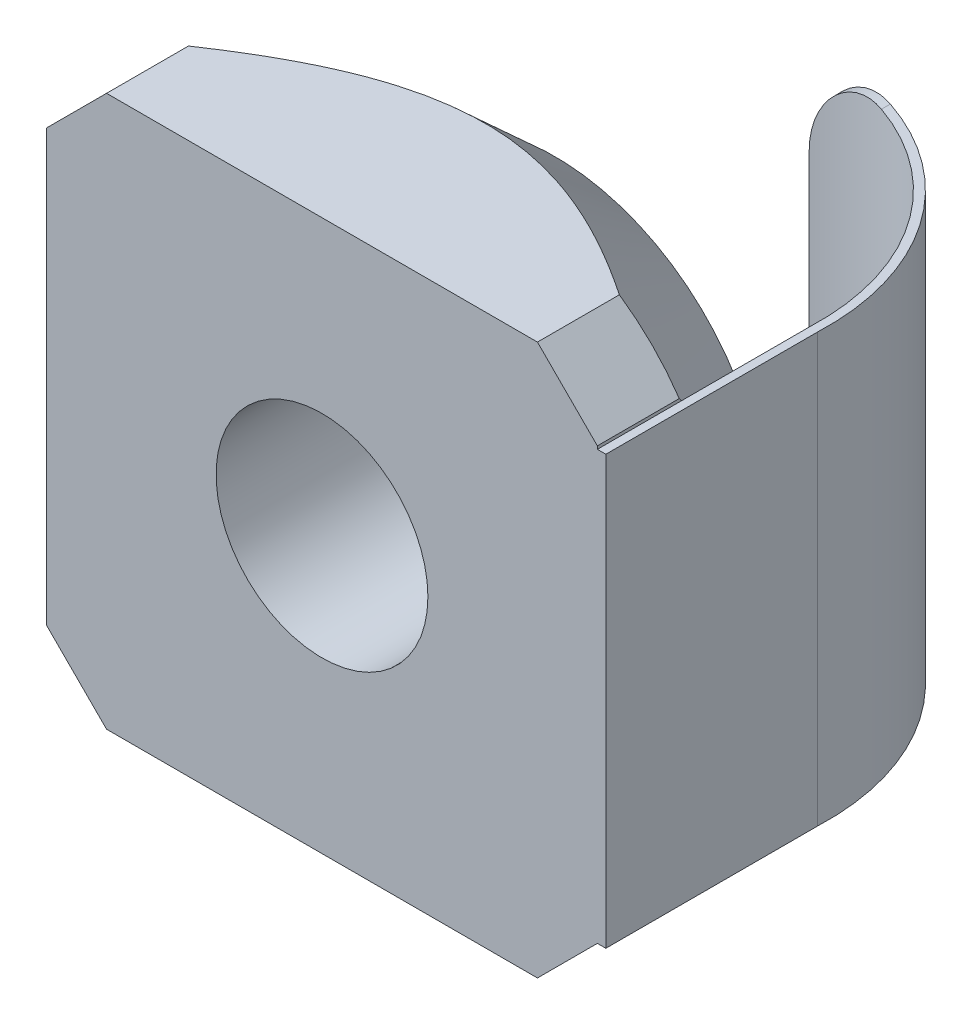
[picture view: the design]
ISO-10303-21;
HEADER;
FILE_DESCRIPTION(('STEP AP214'),'2;1');
FILE_NAME('part.step','',(''),(''),'','','');
FILE_SCHEMA(('AUTOMOTIVE_DESIGN { 1 0 10303 214 1 1 1 1 }'));
ENDSEC;
DATA;
#1=APPLICATION_CONTEXT('core data for automotive mechanical design processes');
#2=APPLICATION_PROTOCOL_DEFINITION('international standard','automotive_design',2000,#1);
#3=PRODUCT_CONTEXT('',#1,'mechanical');
#4=PRODUCT('Part','Part','',(#3));
#5=PRODUCT_RELATED_PRODUCT_CATEGORY('part','',(#4));
#6=PRODUCT_DEFINITION_FORMATION('','',#4);
#7=PRODUCT_DEFINITION_CONTEXT('part definition',#1,'design');
#8=PRODUCT_DEFINITION('design','',#6,#7);
#9=PRODUCT_DEFINITION_SHAPE('','',#8);
#10=(LENGTH_UNIT() NAMED_UNIT(*) SI_UNIT(.MILLI.,.METRE.));
#11=(NAMED_UNIT(*) PLANE_ANGLE_UNIT() SI_UNIT($,.RADIAN.));
#12=(NAMED_UNIT(*) SI_UNIT($,.STERADIAN.) SOLID_ANGLE_UNIT());
#13=UNCERTAINTY_MEASURE_WITH_UNIT(LENGTH_MEASURE(1.E-05),#10,'distance_accuracy_value','');
#14=(GEOMETRIC_REPRESENTATION_CONTEXT(3) GLOBAL_UNCERTAINTY_ASSIGNED_CONTEXT((#13)) GLOBAL_UNIT_ASSIGNED_CONTEXT((#10,
#11,#12)) REPRESENTATION_CONTEXT('',''));
#15=CARTESIAN_POINT('',(0.,0.,0.));
#16=DIRECTION('',(0.,0.,1.));
#17=DIRECTION('',(1.,0.,0.));
#18=AXIS2_PLACEMENT_3D('',#15,#16,#17);
#19=CARTESIAN_POINT('',(0.,0.,-5.5));
#20=DIRECTION('',(0.,0.,1.));
#21=DIRECTION('',(1.,0.,0.));
#22=AXIS2_PLACEMENT_3D('',#19,#20,#21);
#23=PLANE('',#22);
#24=CARTESIAN_POINT('',(0.,0.,-5.5));
#25=DIRECTION('',(0.,0.,1.));
#26=DIRECTION('',(1.,0.,0.));
#27=AXIS2_PLACEMENT_3D('',#24,#25,#26);
#28=CIRCLE('',#27,2.5);
#29=CARTESIAN_POINT('',(2.5,0.,-5.5));
#30=VERTEX_POINT('',#29);
#31=EDGE_CURVE('E327',#30,#30,#28,.T.);
#32=ORIENTED_EDGE('',*,*,#31,.T.);
#33=EDGE_LOOP('',(#32));
#34=FACE_BOUND('',#33,.T.);
#35=CARTESIAN_POINT('',(0.,0.,-5.50000000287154));
#36=DIRECTION('',(0.,0.,1.));
#37=DIRECTION('',(1.,0.,0.));
#38=AXIS2_PLACEMENT_3D('',#35,#36,#37);
#39=CIRCLE('',#38,5.00000000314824);
#40=CARTESIAN_POINT('',(5.00000000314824,0.,-5.50000000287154));
#41=VERTEX_POINT('',#40);
#42=EDGE_CURVE('E288',#41,#41,#39,.T.);
#43=ORIENTED_EDGE('',*,*,#42,.F.);
#44=EDGE_LOOP('',(#43));
#45=FACE_BOUND('',#44,.T.);
#46=ADVANCED_FACE('F30',(#34,#45),#23,.F.);
#47=CARTESIAN_POINT('',(1.13061329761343,-5.08578643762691,-5.23061329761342));
#48=DIRECTION('',(0.,1.,0.));
#49=DIRECTION('',(0.,0.,1.));
#50=AXIS2_PLACEMENT_3D('',#47,#48,#49);
#51=CYLINDRICAL_SURFACE('',#50,5.37433680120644);
#52=DIRECTION('',(0.,1.,0.));
#53=VECTOR('',#52,1.);
#54=CARTESIAN_POINT('',(0.900000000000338,-5.08578643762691,-10.6));
#55=LINE('',#54,#53);
#56=CARTESIAN_POINT('',(0.900000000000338,-3.08578643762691,-10.6));
#57=VERTEX_POINT('',#56);
#58=CARTESIAN_POINT('',(0.900000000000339,3.01421356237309,-10.6));
#59=VERTEX_POINT('',#58);
#60=EDGE_CURVE('E130',#57,#59,#55,.T.);
#61=ORIENTED_EDGE('',*,*,#60,.F.);
#62=CARTESIAN_POINT('',(2.90000000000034,-5.08578643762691,-10.3053316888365));
#63=CARTESIAN_POINT('',(2.84803419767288,-5.08579244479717,-10.3234580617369));
#64=CARTESIAN_POINT('',(2.79577900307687,-5.08376089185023,-10.34077491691));
#65=CARTESIAN_POINT('',(2.69104946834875,-5.07553358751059,-10.3737183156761));
#66=CARTESIAN_POINT('',(2.63857507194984,-5.0693366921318,-10.3893443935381));
#67=CARTESIAN_POINT('',(2.53380993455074,-5.05269177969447,-10.4188209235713));
#68=CARTESIAN_POINT('',(2.48151914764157,-5.04224491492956,-10.4326718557));
#69=CARTESIAN_POINT('',(2.37754341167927,-5.01708267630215,-10.4585706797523));
#70=CARTESIAN_POINT('',(2.32585839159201,-5.00236780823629,-10.4706187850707));
#71=CARTESIAN_POINT('',(2.17211110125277,-4.95174451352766,-10.504107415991));
#72=CARTESIAN_POINT('',(2.07148948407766,-4.90937809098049,-10.5228554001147));
#73=CARTESIAN_POINT('',(1.8778476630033,-4.80832605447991,-10.5536557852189));
#74=CARTESIAN_POINT('',(1.78482256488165,-4.74965105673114,-10.5657125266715));
#75=CARTESIAN_POINT('',(1.61135189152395,-4.61905010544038,-10.5841005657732));
#76=CARTESIAN_POINT('',(1.53066546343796,-4.5474613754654,-10.5905576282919));
#77=CARTESIAN_POINT('',(1.3817294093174,-4.39209571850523,-10.5996001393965));
#78=CARTESIAN_POINT('',(1.31348514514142,-4.30831356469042,-10.602183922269));
#79=CARTESIAN_POINT('',(1.19010431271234,-4.12902241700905,-10.6049836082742));
#80=CARTESIAN_POINT('',(1.13526474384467,-4.03330843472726,-10.605149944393));
#81=CARTESIAN_POINT('',(1.04205250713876,-3.83419182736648,-10.6044227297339));
#82=CARTESIAN_POINT('',(1.00367583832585,-3.7307910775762,-10.6035294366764));
#83=CARTESIAN_POINT('',(0.949511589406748,-3.53731687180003,-10.6019565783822));
#84=CARTESIAN_POINT('',(0.930977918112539,-3.4480009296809,-10.6012666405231));
#85=CARTESIAN_POINT('',(0.906208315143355,-3.26772910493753,-10.6002660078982));
#86=CARTESIAN_POINT('',(0.899965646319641,-3.17677414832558,-10.5999551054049));
#87=CARTESIAN_POINT('',(0.900000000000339,-3.08578643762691,-10.6));
#88=B_SPLINE_CURVE_WITH_KNOTS('',3,(#62,#63,#64,#65,#66,#67,#68,#69,#70,#71,#72,#73,#74,#75,#76,
#77,#78,#79,#80,#81,#82,#83,#84,#85,#86,#87),.UNSPECIFIED.,.F.,.F.,(4,2,2,2,2,2,2,2,2,2,2,2,4),
(0.,0.165074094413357,0.330193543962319,0.495268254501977,0.660323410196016,0.990846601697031,
1.32115513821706,1.64383733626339,1.96665826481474,2.29608914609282,2.625439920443,
2.89827884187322,3.17096816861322),.UNSPECIFIED.);
#89=CARTESIAN_POINT('',(2.90000000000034,-5.08578643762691,-10.3053316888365));
#90=VERTEX_POINT('',#89);
#91=EDGE_CURVE('E136',#90,#57,#88,.T.);
#92=ORIENTED_EDGE('',*,*,#91,.F.);
#93=CARTESIAN_POINT('',(1.13061329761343,-5.08578643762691,-5.23061329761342));
#94=DIRECTION('',(0.,1.,0.));
#95=DIRECTION('',(0.,0.,1.));
#96=AXIS2_PLACEMENT_3D('',#93,#94,#95);
#97=CIRCLE('',#96,5.37433680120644);
#98=CARTESIAN_POINT('',(6.5,-5.08578643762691,-5.));
#99=VERTEX_POINT('',#98);
#100=EDGE_CURVE('E264',#90,#99,#97,.F.);
#101=ORIENTED_EDGE('',*,*,#100,.T.);
#102=DIRECTION('',(0.,1.,0.));
#103=VECTOR('',#102,1.);
#104=CARTESIAN_POINT('',(6.5,-5.08578643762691,-5.00000000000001));
#105=LINE('',#104,#103);
#106=CARTESIAN_POINT('',(6.5,5.01421356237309,-5.00000000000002));
#107=VERTEX_POINT('',#106);
#108=EDGE_CURVE('E137',#107,#99,#105,.F.);
#109=ORIENTED_EDGE('',*,*,#108,.F.);
#110=CARTESIAN_POINT('',(1.13061329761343,5.01421356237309,-5.23061329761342));
#111=DIRECTION('',(0.,1.,0.));
#112=DIRECTION('',(0.,0.,1.));
#113=AXIS2_PLACEMENT_3D('',#110,#111,#112);
#114=CIRCLE('',#113,5.37433680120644);
#115=CARTESIAN_POINT('',(2.90000000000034,5.01421356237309,-10.3053316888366));
#116=VERTEX_POINT('',#115);
#117=EDGE_CURVE('E133',#116,#107,#114,.F.);
#118=ORIENTED_EDGE('',*,*,#117,.F.);
#119=CARTESIAN_POINT('',(0.900000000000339,3.01421356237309,-10.6));
#120=CARTESIAN_POINT('',(0.900000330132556,3.07046535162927,-10.5999949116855));
#121=CARTESIAN_POINT('',(0.902374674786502,3.12669009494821,-10.6001025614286));
#122=CARTESIAN_POINT('',(0.911846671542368,3.23873632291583,-10.6004988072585));
#123=CARTESIAN_POINT('',(0.918944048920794,3.29455783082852,-10.6007873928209));
#124=CARTESIAN_POINT('',(0.947254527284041,3.46073025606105,-10.6018566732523));
#125=CARTESIAN_POINT('',(0.975486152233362,3.56996713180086,-10.6028411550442));
#126=CARTESIAN_POINT('',(1.04988306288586,3.78215272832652,-10.6044710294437));
#127=CARTESIAN_POINT('',(1.0960569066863,3.88509842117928,-10.6051162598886));
#128=CARTESIAN_POINT('',(1.20503246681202,4.08178799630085,-10.6047100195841));
#129=CARTESIAN_POINT('',(1.2678326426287,4.17553272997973,-10.6036587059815));
#130=CARTESIAN_POINT('',(1.40800107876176,4.35081056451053,-10.5982422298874));
#131=CARTESIAN_POINT('',(1.48532101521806,4.43238260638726,-10.593887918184));
#132=CARTESIAN_POINT('',(1.6522600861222,4.58126236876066,-10.58022750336));
#133=CARTESIAN_POINT('',(1.74187515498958,4.64857478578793,-10.5709230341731));
#134=CARTESIAN_POINT('',(1.92817494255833,4.76560487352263,-10.5462505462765));
#135=CARTESIAN_POINT('',(2.02464050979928,4.81570333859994,-10.5310321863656));
#136=CARTESIAN_POINT('',(2.22328367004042,4.89932935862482,-10.4936700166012));
#137=CARTESIAN_POINT('',(2.32546183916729,4.93285523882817,-10.4715255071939));
#138=CARTESIAN_POINT('',(2.50694959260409,4.97686434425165,-10.4263509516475));
#139=CARTESIAN_POINT('',(2.58579039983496,4.99096532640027,-10.4048403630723));
#140=CARTESIAN_POINT('',(2.74330698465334,5.00964641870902,-10.3579469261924));
#141=CARTESIAN_POINT('',(2.82198281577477,5.01424259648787,-10.3325706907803));
#142=CARTESIAN_POINT('',(2.90000000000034,5.01421356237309,-10.3053316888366));
#143=B_SPLINE_CURVE_WITH_KNOTS('',3,(#119,#120,#121,#122,#123,#124,#125,#126,#127,#128,#129,
#130,#131,#132,#133,#134,#135,#136,#137,#138,#139,#140,#141,#142),.UNSPECIFIED.,.F.,.F.,(4,2,2,
2,2,2,2,2,2,2,2,4),(0.,0.168651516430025,0.337293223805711,0.674049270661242,1.01096614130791,
1.3478518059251,1.68363552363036,2.01930847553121,2.34698849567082,2.67470162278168,
2.92287445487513,3.17062741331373),.UNSPECIFIED.);
#144=EDGE_CURVE('E33',#59,#116,#143,.T.);
#145=ORIENTED_EDGE('',*,*,#144,.F.);
#146=EDGE_LOOP('',(#61,#92,#101,#109,#118,#145));
#147=FACE_BOUND('',#146,.T.);
#148=ADVANCED_FACE('F128',(#147),#51,.F.);
#149=CARTESIAN_POINT('',(6.5,-5.08578643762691,0.));
#150=DIRECTION('',(-1.,0.,0.));
#151=DIRECTION('',(0.,0.,1.));
#152=AXIS2_PLACEMENT_3D('',#149,#150,#151);
#153=PLANE('',#152);
#154=ORIENTED_EDGE('',*,*,#108,.T.);
#155=DIRECTION('',(0.,0.,1.));
#156=VECTOR('',#155,1.);
#157=CARTESIAN_POINT('',(6.5,-5.08578643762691,-6.41150462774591));
#158=LINE('',#157,#156);
#159=CARTESIAN_POINT('',(6.5,-5.08578639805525,-1.93333422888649));
#160=VERTEX_POINT('',#159);
#161=EDGE_CURVE('E361',#99,#160,#158,.T.);
#162=ORIENTED_EDGE('',*,*,#161,.T.);
#163=CARTESIAN_POINT('',(6.49999999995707,5.01421356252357,-1.98147651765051));
#164=CARTESIAN_POINT('',(6.49999999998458,4.90089300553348,-2.05735219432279));
#165=CARTESIAN_POINT('',(6.49999999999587,4.78682941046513,-2.13213187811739));
#166=CARTESIAN_POINT('',(6.50000000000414,4.55705300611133,-2.27916665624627));
#167=CARTESIAN_POINT('',(6.50000000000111,4.44133984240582,-2.35142119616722));
#168=CARTESIAN_POINT('',(6.49999999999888,4.2077031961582,-2.49331131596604));
#169=CARTESIAN_POINT('',(6.49999999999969,4.08977293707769,-2.56293578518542));
#170=CARTESIAN_POINT('',(6.50000000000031,3.85200835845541,-2.69883005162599));
#171=CARTESIAN_POINT('',(6.50000000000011,3.73217414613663,-2.76510003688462));
#172=CARTESIAN_POINT('',(6.49999999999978,3.36347781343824,-2.96142749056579));
#173=CARTESIAN_POINT('',(6.49999999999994,3.11129685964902,-3.08537257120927));
#174=CARTESIAN_POINT('',(6.50000000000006,2.59770756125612,-3.31174910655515));
#175=CARTESIAN_POINT('',(6.50000000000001,2.33631394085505,-3.41421322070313));
#176=CARTESIAN_POINT('',(6.49999999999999,1.89822792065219,-3.55997176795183));
#177=CARTESIAN_POINT('',(6.5,1.72423965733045,-3.61138096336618));
#178=CARTESIAN_POINT('',(6.5,1.37277217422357,-3.70067669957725));
#179=CARTESIAN_POINT('',(6.5,1.19529289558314,-3.73856301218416));
#180=CARTESIAN_POINT('',(6.5,0.839667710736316,-3.79880141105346));
#181=CARTESIAN_POINT('',(6.5,0.661549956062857,-3.82131766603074));
#182=CARTESIAN_POINT('',(6.5,0.3040090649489,-3.8503496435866));
#183=CARTESIAN_POINT('',(6.5,0.124586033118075,-3.85686663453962));
#184=CARTESIAN_POINT('',(6.5,-0.234534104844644,-3.85354991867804));
#185=CARTESIAN_POINT('',(6.5,-0.414230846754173,-3.84367725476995));
#186=CARTESIAN_POINT('',(6.5,-0.772032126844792,-3.80803294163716));
#187=CARTESIAN_POINT('',(6.5,-0.950136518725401,-3.78225984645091));
#188=CARTESIAN_POINT('',(6.5,-1.30552029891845,-3.71570927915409));
#189=CARTESIAN_POINT('',(6.5,-1.48276890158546,-3.67476939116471));
#190=CARTESIAN_POINT('',(6.5,-1.83363232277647,-3.57968542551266));
#191=CARTESIAN_POINT('',(6.5,-2.00724719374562,-3.52554153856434));
#192=CARTESIAN_POINT('',(6.5,-2.44147704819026,-3.37423611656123));
#193=CARTESIAN_POINT('',(6.5,-2.69944314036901,-3.2694828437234));
#194=CARTESIAN_POINT('',(6.5,-3.20636233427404,-3.03963560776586));
#195=CARTESIAN_POINT('',(6.5,-3.45530232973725,-2.91451340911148));
#196=CARTESIAN_POINT('',(6.5,-3.9386424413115,-2.65236001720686));
#197=CARTESIAN_POINT('',(6.5,-4.17325100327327,-2.51570956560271));
#198=CARTESIAN_POINT('',(6.5,-4.51960285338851,-2.3026955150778));
#199=CARTESIAN_POINT('',(6.5,-4.63393607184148,-2.23048126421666));
#200=CARTESIAN_POINT('',(6.5,-4.86101206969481,-2.08364094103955));
#201=CARTESIAN_POINT('',(6.5,-4.97375516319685,-2.00901535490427));
#202=CARTESIAN_POINT('',(6.5,-5.08578635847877,-1.93333425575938));
#203=B_SPLINE_CURVE_WITH_KNOTS('',3,(#163,#164,#165,#166,#167,#168,#169,#170,#171,#172,#173,
#174,#175,#176,#177,#178,#179,#180,#181,#182,#183,#184,#185,#186,#187,#188,#189,#190,#191,#192,
#193,#194,#195,#196,#197,#198,#199,#200,#201,#202),.UNSPECIFIED.,.F.,.F.,(4,2,2,2,2,2,2,2,2,2,2,
2,2,2,2,2,2,2,2,4),(0.,0.409135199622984,0.8183596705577,1.2291540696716,1.63992541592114,
2.48215150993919,3.32308765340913,3.86690681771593,4.4107351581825,4.94865991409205,
5.48654202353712,6.02570447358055,6.56491596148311,7.11007693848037,7.6552300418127,
8.48926109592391,9.32445829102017,10.1385545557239,10.5442192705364,10.949802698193),.UNSPECIFIED.);
#204=CARTESIAN_POINT('',(6.5,5.01421356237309,-1.98147651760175));
#205=VERTEX_POINT('',#204);
#206=EDGE_CURVE('E191',#205,#160,#203,.T.);
#207=ORIENTED_EDGE('',*,*,#206,.F.);
#208=DIRECTION('',(0.,0.,1.));
#209=VECTOR('',#208,1.);
#210=CARTESIAN_POINT('',(6.5,5.01421356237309,-6.41150462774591));
#211=LINE('',#210,#209);
#212=EDGE_CURVE('E294',#107,#205,#211,.T.);
#213=ORIENTED_EDGE('',*,*,#212,.F.);
#214=EDGE_LOOP('',(#154,#162,#207,#213));
#215=FACE_BOUND('',#214,.T.);
#216=ADVANCED_FACE('F269',(#215),#153,.T.);
#217=CARTESIAN_POINT('',(2.90000000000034,3.01421356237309,-8.50575231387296));
#218=DIRECTION('',(0.,0.,-1.));
#219=DIRECTION('',(0.,1.,0.));
#220=AXIS2_PLACEMENT_3D('',#217,#218,#219);
#221=CYLINDRICAL_SURFACE('',#220,2.);
#222=ORIENTED_EDGE('',*,*,#144,.T.);
#223=DIRECTION('',(0.,0.,1.));
#224=VECTOR('',#223,1.);
#225=CARTESIAN_POINT('',(2.90000000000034,5.01421356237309,-6.41150462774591));
#226=LINE('',#225,#224);
#227=CARTESIAN_POINT('',(2.90000000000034,5.01421356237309,-10.5164927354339));
#228=VERTEX_POINT('',#227);
#229=EDGE_CURVE('E291',#228,#116,#226,.T.);
#230=ORIENTED_EDGE('',*,*,#229,.F.);
#231=CARTESIAN_POINT('',(0.900000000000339,3.01421356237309,-10.8));
#232=CARTESIAN_POINT('',(0.90000033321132,3.07046660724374,-10.7999950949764));
#233=CARTESIAN_POINT('',(0.902374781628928,3.12669261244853,-10.8000988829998));
#234=CARTESIAN_POINT('',(0.911847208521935,3.2387414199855,-10.8004809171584));
#235=CARTESIAN_POINT('',(0.918944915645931,3.29456424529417,-10.8007591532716));
#236=CARTESIAN_POINT('',(0.947256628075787,3.46073994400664,-10.8017900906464));
#237=CARTESIAN_POINT('',(0.975489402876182,3.56997882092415,-10.8027392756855));
#238=CARTESIAN_POINT('',(1.04988921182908,3.78216784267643,-10.8043106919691));
#239=CARTESIAN_POINT('',(1.09606480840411,3.88511495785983,-10.8049327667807));
#240=CARTESIAN_POINT('',(1.20504374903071,4.08180608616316,-10.8045408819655));
#241=CARTESIAN_POINT('',(1.2678454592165,4.17555100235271,-10.8035270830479));
#242=CARTESIAN_POINT('',(1.40803624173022,4.35085229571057,-10.7983038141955));
#243=CARTESIAN_POINT('',(1.48538034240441,4.43244489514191,-10.7941040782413));
#244=CARTESIAN_POINT('',(1.65239289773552,4.58137143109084,-10.7809278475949));
#245=CARTESIAN_POINT('',(1.74205772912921,4.64870954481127,-10.7719527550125));
#246=CARTESIAN_POINT('',(1.92866159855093,4.76589089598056,-10.748131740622));
#247=CARTESIAN_POINT('',(2.02539514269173,4.81608909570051,-10.7334204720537));
#248=CARTESIAN_POINT('',(2.22467295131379,4.89984546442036,-10.6972870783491));
#249=CARTESIAN_POINT('',(2.32721752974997,4.93340273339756,-10.6758645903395));
#250=CARTESIAN_POINT('',(2.50869878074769,4.97719479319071,-10.632328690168));
#251=CARTESIAN_POINT('',(2.58712849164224,4.99116285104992,-10.611726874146));
#252=CARTESIAN_POINT('',(2.74390539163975,5.00967798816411,-10.5668354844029));
#253=CARTESIAN_POINT('',(2.82225249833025,5.01424083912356,-10.5425521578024));
#254=CARTESIAN_POINT('',(2.90000000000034,5.01421356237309,-10.5164927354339));
#255=B_SPLINE_CURVE_WITH_KNOTS('',3,(#231,#232,#233,#234,#235,#236,#237,#238,#239,#240,#241,
#242,#243,#244,#245,#246,#247,#248,#249,#250,#251,#252,#253,#254),.UNSPECIFIED.,.F.,.F.,(4,2,2,
2,2,2,2,2,2,2,2,4),(0.,0.168655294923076,0.337300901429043,0.674062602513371,1.01098520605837,
1.34787471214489,1.68373904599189,2.01950481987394,2.34782208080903,2.67615709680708,
2.92240952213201,3.16824866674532),.UNSPECIFIED.);
#256=CARTESIAN_POINT('',(0.90000000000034,3.01421356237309,-10.8));
#257=VERTEX_POINT('',#256);
#258=EDGE_CURVE('E142',#257,#228,#255,.T.);
#259=ORIENTED_EDGE('',*,*,#258,.F.);
#260=DIRECTION('',(0.,0.,1.));
#261=VECTOR('',#260,1.);
#262=CARTESIAN_POINT('',(0.900000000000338,3.01421356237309,-10.6));
#263=LINE('',#262,#261);
#264=EDGE_CURVE('E139',#59,#257,#263,.F.);
#265=ORIENTED_EDGE('',*,*,#264,.F.);
#266=EDGE_LOOP('',(#222,#230,#259,#265));
#267=FACE_BOUND('',#266,.T.);
#268=ADVANCED_FACE('F140',(#267),#221,.T.);
#269=CARTESIAN_POINT('',(2.90000000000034,-3.08578643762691,-8.50575231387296));
#270=DIRECTION('',(0.,0.,-1.));
#271=DIRECTION('',(0.,1.,0.));
#272=AXIS2_PLACEMENT_3D('',#269,#270,#271);
#273=CYLINDRICAL_SURFACE('',#272,2.);
#274=ORIENTED_EDGE('',*,*,#91,.T.);
#275=DIRECTION('',(0.,0.,1.));
#276=VECTOR('',#275,1.);
#277=CARTESIAN_POINT('',(0.900000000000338,-3.08578643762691,-10.6));
#278=LINE('',#277,#276);
#279=CARTESIAN_POINT('',(0.900000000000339,-3.08578643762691,-10.8));
#280=VERTEX_POINT('',#279);
#281=EDGE_CURVE('E146',#280,#57,#278,.T.);
#282=ORIENTED_EDGE('',*,*,#281,.F.);
#283=CARTESIAN_POINT('',(2.90000000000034,-5.08578643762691,-10.5164927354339));
#284=CARTESIAN_POINT('',(2.84773330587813,-5.08579243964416,-10.5339958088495));
#285=CARTESIAN_POINT('',(2.7951967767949,-5.08373738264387,-10.5507123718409));
#286=CARTESIAN_POINT('',(2.68994638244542,-5.07542438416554,-10.5825039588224));
#287=CARTESIAN_POINT('',(2.63723247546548,-5.06916537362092,-10.5975785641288));
#288=CARTESIAN_POINT('',(2.53203314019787,-5.05236625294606,-10.6260042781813));
#289=CARTESIAN_POINT('',(2.47954764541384,-5.04182748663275,-10.6393559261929));
#290=CARTESIAN_POINT('',(2.37522367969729,-5.01645900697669,-10.6643117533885));
#291=CARTESIAN_POINT('',(2.3233851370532,-5.00162977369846,-10.6759161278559));
#292=CARTESIAN_POINT('',(2.16924708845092,-4.95064339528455,-10.7081555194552));
#293=CARTESIAN_POINT('',(2.06844710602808,-4.90800669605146,-10.7261843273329));
#294=CARTESIAN_POINT('',(1.87457099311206,-4.80639248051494,-10.7557763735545));
#295=CARTESIAN_POINT('',(1.78149015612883,-4.7474250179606,-10.7673435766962));
#296=CARTESIAN_POINT('',(1.60786619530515,-4.6161382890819,-10.7849753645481));
#297=CARTESIAN_POINT('',(1.52709626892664,-4.54413384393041,-10.791153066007));
#298=CARTESIAN_POINT('',(1.37811156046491,-4.38790607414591,-10.7997766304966));
#299=CARTESIAN_POINT('',(1.30990199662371,-4.30367769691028,-10.8022209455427));
#300=CARTESIAN_POINT('',(1.18678163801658,-4.12357808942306,-10.8048373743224));
#301=CARTESIAN_POINT('',(1.13215296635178,-4.02751350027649,-10.8049647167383));
#302=CARTESIAN_POINT('',(1.03944887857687,-3.82772407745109,-10.8042200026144));
#303=CARTESIAN_POINT('',(1.00136905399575,-3.72400129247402,-10.8033482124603));
#304=CARTESIAN_POINT('',(0.948189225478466,-3.53131953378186,-10.8018401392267));
#305=CARTESIAN_POINT('',(0.930148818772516,-3.4431591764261,-10.8011900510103));
#306=CARTESIAN_POINT('',(0.906041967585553,-3.26527166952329,-10.8002496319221));
#307=CARTESIAN_POINT('',(0.899968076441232,-3.1755455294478,-10.7999590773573));
#308=CARTESIAN_POINT('',(0.900000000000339,-3.08578643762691,-10.8));
#309=B_SPLINE_CURVE_WITH_KNOTS('',3,(#283,#284,#285,#286,#287,#288,#289,#290,#291,#292,#293,
#294,#295,#296,#297,#298,#299,#300,#301,#302,#303,#304,#305,#306,#307,#308),.UNSPECIFIED.,.F.,
.F.,(4,2,2,2,2,2,2,2,2,2,2,2,4),(0.,0.165322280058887,0.330686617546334,0.495999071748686,
0.661293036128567,0.992258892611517,1.32302144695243,1.64666220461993,1.97043711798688,
2.30046189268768,2.63039869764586,2.89957755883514,3.1685888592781),.UNSPECIFIED.);
#310=CARTESIAN_POINT('',(2.90000000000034,-5.08578643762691,-10.5164927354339));
#311=VERTEX_POINT('',#310);
#312=EDGE_CURVE('E237',#311,#280,#309,.T.);
#313=ORIENTED_EDGE('',*,*,#312,.F.);
#314=DIRECTION('',(0.,0.,1.));
#315=VECTOR('',#314,1.);
#316=CARTESIAN_POINT('',(2.90000000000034,-5.08578643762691,-6.41150462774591));
#317=LINE('',#316,#315);
#318=EDGE_CURVE('E263',#311,#90,#317,.T.);
#319=ORIENTED_EDGE('',*,*,#318,.T.);
#320=EDGE_LOOP('',(#274,#282,#313,#319));
#321=FACE_BOUND('',#320,.T.);
#322=ADVANCED_FACE('F268',(#321),#273,.T.);
#323=CARTESIAN_POINT('',(0.900000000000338,-5.08578643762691,-10.6));
#324=DIRECTION('',(-1.,0.,0.));
#325=DIRECTION('',(0.,0.,1.));
#326=AXIS2_PLACEMENT_3D('',#323,#324,#325);
#327=PLANE('',#326);
#328=ORIENTED_EDGE('',*,*,#281,.T.);
#329=ORIENTED_EDGE('',*,*,#60,.T.);
#330=ORIENTED_EDGE('',*,*,#264,.T.);
#331=DIRECTION('',(0.,1.,0.));
#332=VECTOR('',#331,1.);
#333=CARTESIAN_POINT('',(0.90000000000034,-5.08578643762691,-10.8));
#334=LINE('',#333,#332);
#335=EDGE_CURVE('E236',#280,#257,#334,.T.);
#336=ORIENTED_EDGE('',*,*,#335,.F.);
#337=EDGE_LOOP('',(#328,#329,#330,#336));
#338=FACE_BOUND('',#337,.T.);
#339=ADVANCED_FACE('F148',(#338),#327,.T.);
#340=CARTESIAN_POINT('',(6.5,-5.08578643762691,0.));
#341=DIRECTION('',(1.,0.,0.));
#342=DIRECTION('',(0.,0.,-1.));
#343=AXIS2_PLACEMENT_3D('',#340,#341,#342);
#344=PLANE('',#343);
#345=DIRECTION('',(0.,0.,1.));
#346=VECTOR('',#345,1.);
#347=CARTESIAN_POINT('',(6.5,5.08578643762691,0.));
#348=LINE('',#347,#346);
#349=CARTESIAN_POINT('',(6.5,5.08578643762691,0.));
#350=VERTEX_POINT('',#349);
#351=CARTESIAN_POINT('',(6.50000000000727,5.08578643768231,-1.93333420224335));
#352=VERTEX_POINT('',#351);
#353=EDGE_CURVE('E235',#350,#352,#348,.F.);
#354=ORIENTED_EDGE('',*,*,#353,.F.);
#355=DIRECTION('',(0.,1.,0.));
#356=VECTOR('',#355,1.);
#357=CARTESIAN_POINT('',(6.5,-5.08578643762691,0.));
#358=LINE('',#357,#356);
#359=CARTESIAN_POINT('',(6.5,5.01421356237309,0.));
#360=VERTEX_POINT('',#359);
#361=EDGE_CURVE('E149',#350,#360,#358,.F.);
#362=ORIENTED_EDGE('',*,*,#361,.T.);
#363=DIRECTION('',(0.,0.,1.));
#364=VECTOR('',#363,1.);
#365=CARTESIAN_POINT('',(6.5,5.01421356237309,-6.41150462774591));
#366=LINE('',#365,#364);
#367=EDGE_CURVE('E156',#205,#360,#366,.T.);
#368=ORIENTED_EDGE('',*,*,#367,.F.);
#369=CARTESIAN_POINT('',(6.49999999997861,5.08578643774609,-1.93333420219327));
#370=CARTESIAN_POINT('',(6.4999999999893,5.07387404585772,-1.94138233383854));
#371=CARTESIAN_POINT('',(6.49999999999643,5.0619534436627,-1.94941825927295));
#372=CARTESIAN_POINT('',(6.50000000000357,5.03809581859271,-1.96546569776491));
#373=CARTESIAN_POINT('',(6.50000000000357,5.02615879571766,-1.9734772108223));
#374=CARTESIAN_POINT('',(6.5,5.01421356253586,-1.98147651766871));
#375=B_SPLINE_CURVE_WITH_KNOTS('',3,(#369,#370,#371,#372,#373,#374),.UNSPECIFIED.,.F.,.F.,(4,2,
4),(0.,0.0431287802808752,0.0862575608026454),.UNSPECIFIED.);
#376=EDGE_CURVE('E151',#352,#205,#375,.T.);
#377=ORIENTED_EDGE('',*,*,#376,.F.);
#378=EDGE_LOOP('',(#354,#362,#368,#377));
#379=FACE_BOUND('',#378,.T.);
#380=ADVANCED_FACE('F183',(#379),#344,.T.);
#381=CARTESIAN_POINT('',(0.,0.,-1.91193420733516));
#382=DIRECTION('',(0.,0.,1.));
#383=DIRECTION('',(1.,0.,0.));
#384=AXIS2_PLACEMENT_3D('',#381,#382,#383);
#385=CONICAL_SURFACE('',#384,8.27271392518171,0.739466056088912);
#386=ORIENTED_EDGE('',*,*,#42,.T.);
#387=EDGE_LOOP('',(#386));
#388=FACE_BOUND('',#387,.T.);
#389=CARTESIAN_POINT('',(-6.49999999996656,5.08578643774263,-1.93333420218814));
#390=CARTESIAN_POINT('',(-6.49999999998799,4.97217656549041,-2.01007902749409));
#391=CARTESIAN_POINT('',(-6.49999999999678,4.85782950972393,-2.08574579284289));
#392=CARTESIAN_POINT('',(-6.50000000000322,4.62749756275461,-2.23459577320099));
#393=CARTESIAN_POINT('',(-6.50000000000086,4.51151233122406,-2.30777846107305));
#394=CARTESIAN_POINT('',(-6.49999999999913,4.27735001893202,-2.45156937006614));
#395=CARTESIAN_POINT('',(-6.49999999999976,4.15916634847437,-2.52216690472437));
#396=CARTESIAN_POINT('',(-6.50000000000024,3.92090179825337,-2.66006146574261));
#397=CARTESIAN_POINT('',(-6.50000000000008,3.80082102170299,-2.72735867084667));
#398=CARTESIAN_POINT('',(-6.49999999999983,3.43117049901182,-2.927024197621));
#399=CARTESIAN_POINT('',(-6.49999999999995,3.17828163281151,-3.05336340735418));
#400=CARTESIAN_POINT('',(-6.50000000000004,2.66320472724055,-3.2847897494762));
#401=CARTESIAN_POINT('',(-6.50000000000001,2.40103115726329,-3.38990837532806));
#402=CARTESIAN_POINT('',(-6.49999999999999,1.96194937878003,-3.54007016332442));
#403=CARTESIAN_POINT('',(-6.5,1.78780916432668,-3.5931930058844));
#404=CARTESIAN_POINT('',(-6.5,1.43593803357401,-3.68604206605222));
#405=CARTESIAN_POINT('',(-6.5,1.25820705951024,-3.72576806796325));
#406=CARTESIAN_POINT('',(-6.5,0.901971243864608,-3.78972854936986));
#407=CARTESIAN_POINT('',(-6.5,0.723496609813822,-3.81412921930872));
#408=CARTESIAN_POINT('',(-6.5,0.365074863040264,-3.84691624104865));
#409=CARTESIAN_POINT('',(-6.5,0.185127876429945,-3.85530395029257));
#410=CARTESIAN_POINT('',(-6.5,-0.175331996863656,-3.85561829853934));
#411=CARTESIAN_POINT('',(-6.5,-0.355844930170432,-3.84749448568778));
#412=CARTESIAN_POINT('',(-6.5,-0.715412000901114,-3.81512247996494));
#413=CARTESIAN_POINT('',(-6.5,-0.894466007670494,-3.79087285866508));
#414=CARTESIAN_POINT('',(-6.5,-1.25186987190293,-3.72710369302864));
#415=CARTESIAN_POINT('',(-6.5,-1.43018938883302,-3.6874161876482));
#416=CARTESIAN_POINT('',(-6.5,-1.7832209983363,-3.59454247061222));
#417=CARTESIAN_POINT('',(-6.5,-1.95793314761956,-3.54135647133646));
#418=CARTESIAN_POINT('',(-6.5,-2.39791270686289,-3.39110767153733));
#419=CARTESIAN_POINT('',(-6.5,-2.66041462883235,-3.2859613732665));
#420=CARTESIAN_POINT('',(-6.5,-3.17612601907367,-3.05441341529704));
#421=CARTESIAN_POINT('',(-6.5,-3.4293209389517,-2.92798006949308));
#422=CARTESIAN_POINT('',(-6.5,-3.79940591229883,-2.72814379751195));
#423=CARTESIAN_POINT('',(-6.5,-3.91962359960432,-2.66078705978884));
#424=CARTESIAN_POINT('',(-6.5,-4.15815744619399,-2.52276484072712));
#425=CARTESIAN_POINT('',(-6.5,-4.27647350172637,-2.45209917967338));
#426=CARTESIAN_POINT('',(-6.5,-4.510894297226,-2.30816632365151));
#427=CARTESIAN_POINT('',(-6.5,-4.62700566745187,-2.23490988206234));
#428=CARTESIAN_POINT('',(-6.5,-4.85758619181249,-2.08590677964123));
#429=CARTESIAN_POINT('',(-6.5,-4.97205568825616,-2.01016064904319));
#430=CARTESIAN_POINT('',(-6.5,-5.08578643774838,-1.93333420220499));
#431=B_SPLINE_CURVE_WITH_KNOTS('',3,(#389,#390,#391,#392,#393,#394,#395,#396,#397,#398,#399,
#400,#401,#402,#403,#404,#405,#406,#407,#408,#409,#410,#411,#412,#413,#414,#415,#416,#417,#418,
#419,#420,#421,#422,#423,#424,#425,#426,#427,#428,#429,#430),.UNSPECIFIED.,.F.,.F.,(4,2,2,2,2,2,
2,2,2,2,2,2,2,2,2,2,2,2,2,2,4),(0.,0.41131042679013,0.822707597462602,1.23564791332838,
1.64856583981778,2.49590493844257,3.34197710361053,3.88772071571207,4.43347311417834,
4.97320018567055,5.51288150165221,6.05421432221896,6.59559510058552,7.1430386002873,
7.69047348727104,8.53748456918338,9.38576777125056,9.79913116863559,10.2125170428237,
10.6243522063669,11.0361002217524),.UNSPECIFIED.);
#432=CARTESIAN_POINT('',(-6.50000000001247,5.08578643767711,-1.93333420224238));
#433=VERTEX_POINT('',#432);
#434=CARTESIAN_POINT('',(-6.50000000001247,-5.08578643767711,-1.93333420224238));
#435=VERTEX_POINT('',#434);
#436=EDGE_CURVE('E209',#433,#435,#431,.T.);
#437=ORIENTED_EDGE('',*,*,#436,.F.);
#438=CARTESIAN_POINT('',(-5.08578643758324,6.50000000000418,-1.93333420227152));
#439=CARTESIAN_POINT('',(-5.20320338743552,6.38258305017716,-1.95544496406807));
#440=CARTESIAN_POINT('',(-5.32114245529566,6.26464398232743,-1.97213629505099));
#441=CARTESIAN_POINT('',(-5.55702028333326,6.02876615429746,-1.99438943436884));
#442=CARTESIAN_POINT('',(-5.6749567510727,5.9108296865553,-2.00000000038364));
#443=CARTESIAN_POINT('',(-5.91082968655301,5.67495675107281,-2.00000000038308));
#444=CARTESIAN_POINT('',(-6.02876615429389,5.55702028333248,-1.99438943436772));
#445=CARTESIAN_POINT('',(-6.2646439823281,5.32114245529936,-1.97213629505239));
#446=CARTESIAN_POINT('',(-6.38258305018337,5.20320338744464,-1.95544496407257));
#447=CARTESIAN_POINT('',(-6.50000000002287,5.08578643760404,-1.93333420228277));
#448=B_SPLINE_CURVE_WITH_KNOTS('',3,(#438,#439,#440,#441,#442,#443,#444,#445,#446,#447),
.UNSPECIFIED.,.F.,.F.,(4,2,2,2,4),(0.,0.502492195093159,1.00276834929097,1.50304450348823,
2.00553669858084),.UNSPECIFIED.);
#449=CARTESIAN_POINT('',(-5.08578643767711,6.50000000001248,-1.93333420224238));
#450=VERTEX_POINT('',#449);
#451=EDGE_CURVE('E216',#450,#433,#448,.T.);
#452=ORIENTED_EDGE('',*,*,#451,.F.);
#453=CARTESIAN_POINT('',(5.08578643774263,6.49999999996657,-1.93333420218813));
#454=CARTESIAN_POINT('',(4.9721765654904,6.49999999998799,-2.01007902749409));
#455=CARTESIAN_POINT('',(4.85782950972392,6.49999999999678,-2.08574579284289));
#456=CARTESIAN_POINT('',(4.62749756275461,6.50000000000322,-2.23459577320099));
#457=CARTESIAN_POINT('',(4.51151233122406,6.50000000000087,-2.30777846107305));
#458=CARTESIAN_POINT('',(4.27735001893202,6.49999999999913,-2.45156937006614));
#459=CARTESIAN_POINT('',(4.15916634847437,6.49999999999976,-2.52216690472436));
#460=CARTESIAN_POINT('',(3.92090179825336,6.50000000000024,-2.66006146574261));
#461=CARTESIAN_POINT('',(3.80082102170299,6.50000000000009,-2.72735867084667));
#462=CARTESIAN_POINT('',(3.43117049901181,6.49999999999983,-2.927024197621));
#463=CARTESIAN_POINT('',(3.17828163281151,6.49999999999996,-3.05336340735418));
#464=CARTESIAN_POINT('',(2.66320472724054,6.50000000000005,-3.2847897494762));
#465=CARTESIAN_POINT('',(2.40103115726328,6.50000000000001,-3.38990837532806));
#466=CARTESIAN_POINT('',(1.96194937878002,6.5,-3.54007016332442));
#467=CARTESIAN_POINT('',(1.78780916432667,6.5,-3.5931930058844));
#468=CARTESIAN_POINT('',(1.435938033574,6.50000000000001,-3.68604206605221));
#469=CARTESIAN_POINT('',(1.25820705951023,6.5,-3.72576806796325));
#470=CARTESIAN_POINT('',(0.901971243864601,6.5,-3.78972854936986));
#471=CARTESIAN_POINT('',(0.723496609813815,6.5,-3.81412921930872));
#472=CARTESIAN_POINT('',(0.365074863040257,6.5,-3.84691624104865));
#473=CARTESIAN_POINT('',(0.185127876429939,6.5,-3.85530395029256));
#474=CARTESIAN_POINT('',(-0.175331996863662,6.5,-3.85561829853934));
#475=CARTESIAN_POINT('',(-0.355844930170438,6.5,-3.84749448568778));
#476=CARTESIAN_POINT('',(-0.715412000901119,6.5,-3.81512247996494));
#477=CARTESIAN_POINT('',(-0.8944660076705,6.5,-3.79087285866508));
#478=CARTESIAN_POINT('',(-1.25186987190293,6.5,-3.72710369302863));
#479=CARTESIAN_POINT('',(-1.43018938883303,6.5,-3.68741618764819));
#480=CARTESIAN_POINT('',(-1.7832209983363,6.5,-3.59454247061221));
#481=CARTESIAN_POINT('',(-1.95793314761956,6.5,-3.54135647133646));
#482=CARTESIAN_POINT('',(-2.3979127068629,6.5,-3.39110767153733));
#483=CARTESIAN_POINT('',(-2.66041462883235,6.5,-3.2859613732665));
#484=CARTESIAN_POINT('',(-3.17612601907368,6.5,-3.05441341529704));
#485=CARTESIAN_POINT('',(-3.4293209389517,6.5,-2.92798006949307));
#486=CARTESIAN_POINT('',(-3.79940591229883,6.5,-2.72814379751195));
#487=CARTESIAN_POINT('',(-3.91962359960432,6.5,-2.66078705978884));
#488=CARTESIAN_POINT('',(-4.15815744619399,6.5,-2.52276484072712));
#489=CARTESIAN_POINT('',(-4.27647350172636,6.5,-2.45209917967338));
#490=CARTESIAN_POINT('',(-4.510894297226,6.5,-2.30816632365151));
#491=CARTESIAN_POINT('',(-4.62700566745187,6.5,-2.23490988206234));
#492=CARTESIAN_POINT('',(-4.85758619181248,6.5,-2.08590677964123));
#493=CARTESIAN_POINT('',(-4.97205568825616,6.5,-2.01016064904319));
#494=CARTESIAN_POINT('',(-5.08578643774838,6.5,-1.93333420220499));
#495=B_SPLINE_CURVE_WITH_KNOTS('',3,(#453,#454,#455,#456,#457,#458,#459,#460,#461,#462,#463,
#464,#465,#466,#467,#468,#469,#470,#471,#472,#473,#474,#475,#476,#477,#478,#479,#480,#481,#482,
#483,#484,#485,#486,#487,#488,#489,#490,#491,#492,#493,#494),.UNSPECIFIED.,.F.,.F.,(4,2,2,2,2,2,
2,2,2,2,2,2,2,2,2,2,2,2,2,2,4),(0.,0.411310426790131,0.822707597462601,1.23564791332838,
1.64856583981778,2.49590493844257,3.34197710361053,3.88772071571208,4.43347311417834,
4.97320018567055,5.51288150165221,6.05421432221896,6.59559510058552,7.1430386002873,
7.69047348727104,8.53748456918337,9.38576777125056,9.79913116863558,10.2125170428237,
10.6243522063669,11.0361002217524),.UNSPECIFIED.);
#496=CARTESIAN_POINT('',(5.08578643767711,6.50000000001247,-1.93333420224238));
#497=VERTEX_POINT('',#496);
#498=EDGE_CURVE('E222',#497,#450,#495,.T.);
#499=ORIENTED_EDGE('',*,*,#498,.F.);
#500=CARTESIAN_POINT('',(6.50000000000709,5.08578643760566,-1.93333420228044));
#501=CARTESIAN_POINT('',(6.38258305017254,5.20320338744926,-1.95544496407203));
#502=CARTESIAN_POINT('',(6.26464398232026,5.32114245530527,-1.97213629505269));
#503=CARTESIAN_POINT('',(6.02876615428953,5.55702028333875,-1.99438943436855));
#504=CARTESIAN_POINT('',(5.91082968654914,5.67495675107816,-2.0000000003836));
#505=CARTESIAN_POINT('',(5.67495675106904,5.91082968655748,-2.00000000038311));
#506=CARTESIAN_POINT('',(5.55702028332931,6.0287661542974,-1.99438943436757));
#507=CARTESIAN_POINT('',(5.32114245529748,6.26464398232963,-1.97213629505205));
#508=CARTESIAN_POINT('',(5.20320338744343,6.38258305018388,-1.95544496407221));
#509=CARTESIAN_POINT('',(5.08578643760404,6.50000000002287,-1.93333420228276));
#510=B_SPLINE_CURVE_WITH_KNOTS('',3,(#500,#501,#502,#503,#504,#505,#506,#507,#508,#509),
.UNSPECIFIED.,.F.,.F.,(4,2,2,2,4),(0.,0.502492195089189,1.00276834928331,1.50304450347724,
2.00553669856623),.UNSPECIFIED.);
#511=EDGE_CURVE('E228',#352,#497,#510,.T.);
#512=ORIENTED_EDGE('',*,*,#511,.F.);
#513=ORIENTED_EDGE('',*,*,#376,.T.);
#514=ORIENTED_EDGE('',*,*,#206,.T.);
#515=CARTESIAN_POINT('',(5.08578643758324,-6.50000000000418,-1.93333420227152));
#516=CARTESIAN_POINT('',(5.2032033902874,-6.38258304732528,-1.95544496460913));
#517=CARTESIAN_POINT('',(5.32114246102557,-6.26464397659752,-1.97213629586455));
#518=CARTESIAN_POINT('',(5.55702029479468,-6.02876614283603,-1.99438943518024));
#519=CARTESIAN_POINT('',(5.67495676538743,-5.91082967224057,-2.00000000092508));
#520=CARTESIAN_POINT('',(5.91082970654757,-5.67495673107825,-1.99999999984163));
#521=CARTESIAN_POINT('',(6.02876617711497,-5.5570202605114,-1.99438943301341));
#522=CARTESIAN_POINT('',(6.26464401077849,-5.32114242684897,-1.97213629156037));
#523=CARTESIAN_POINT('',(6.38258308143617,-5.20320335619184,-1.95544495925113));
#524=CARTESIAN_POINT('',(6.50000003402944,-5.08578640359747,-1.93333419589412));
#525=B_SPLINE_CURVE_WITH_KNOTS('',3,(#515,#516,#517,#518,#519,#520,#521,#522,#523,#524),
.UNSPECIFIED.,.F.,.F.,(4,2,2,2,4),(0.,0.502492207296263,1.0027683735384,1.50304453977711,
2.00553674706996),.UNSPECIFIED.);
#526=CARTESIAN_POINT('',(5.08578643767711,-6.50000000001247,-1.93333420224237));
#527=VERTEX_POINT('',#526);
#528=EDGE_CURVE('E158',#527,#160,#525,.T.);
#529=ORIENTED_EDGE('',*,*,#528,.F.);
#530=CARTESIAN_POINT('',(-5.08578643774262,-6.49999999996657,-1.93333420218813));
#531=CARTESIAN_POINT('',(-4.9721765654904,-6.49999999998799,-2.01007902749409));
#532=CARTESIAN_POINT('',(-4.85782950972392,-6.49999999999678,-2.08574579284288));
#533=CARTESIAN_POINT('',(-4.62749756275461,-6.50000000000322,-2.23459577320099));
#534=CARTESIAN_POINT('',(-4.51151233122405,-6.50000000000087,-2.30777846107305));
#535=CARTESIAN_POINT('',(-4.27735001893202,-6.49999999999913,-2.45156937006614));
#536=CARTESIAN_POINT('',(-4.15916634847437,-6.49999999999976,-2.52216690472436));
#537=CARTESIAN_POINT('',(-3.92090179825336,-6.50000000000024,-2.6600614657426));
#538=CARTESIAN_POINT('',(-3.80082102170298,-6.50000000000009,-2.72735867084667));
#539=CARTESIAN_POINT('',(-3.43117049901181,-6.49999999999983,-2.927024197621));
#540=CARTESIAN_POINT('',(-3.1782816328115,-6.49999999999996,-3.05336340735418));
#541=CARTESIAN_POINT('',(-2.66320472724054,-6.50000000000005,-3.2847897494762));
#542=CARTESIAN_POINT('',(-2.40103115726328,-6.50000000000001,-3.38990837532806));
#543=CARTESIAN_POINT('',(-1.96194937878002,-6.5,-3.54007016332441));
#544=CARTESIAN_POINT('',(-1.78780916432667,-6.5,-3.5931930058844));
#545=CARTESIAN_POINT('',(-1.435938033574,-6.5,-3.68604206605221));
#546=CARTESIAN_POINT('',(-1.25820705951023,-6.5,-3.72576806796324));
#547=CARTESIAN_POINT('',(-0.9019712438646,-6.5,-3.78972854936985));
#548=CARTESIAN_POINT('',(-0.723496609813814,-6.5,-3.81412921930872));
#549=CARTESIAN_POINT('',(-0.365074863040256,-6.5,-3.84691624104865));
#550=CARTESIAN_POINT('',(-0.185127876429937,-6.5,-3.85530395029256));
#551=CARTESIAN_POINT('',(0.175331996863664,-6.5,-3.85561829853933));
#552=CARTESIAN_POINT('',(0.35584493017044,-6.5,-3.84749448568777));
#553=CARTESIAN_POINT('',(0.715412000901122,-6.5,-3.81512247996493));
#554=CARTESIAN_POINT('',(0.894466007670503,-6.5,-3.79087285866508));
#555=CARTESIAN_POINT('',(1.25186987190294,-6.5,-3.72710369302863));
#556=CARTESIAN_POINT('',(1.43018938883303,-6.5,-3.68741618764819));
#557=CARTESIAN_POINT('',(1.7832209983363,-6.5,-3.59454247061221));
#558=CARTESIAN_POINT('',(1.95793314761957,-6.5,-3.54135647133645));
#559=CARTESIAN_POINT('',(2.3979127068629,-6.5,-3.39110767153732));
#560=CARTESIAN_POINT('',(2.66041462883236,-6.5,-3.28596137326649));
#561=CARTESIAN_POINT('',(3.17612601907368,-6.5,-3.05441341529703));
#562=CARTESIAN_POINT('',(3.42932093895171,-6.5,-2.92798006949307));
#563=CARTESIAN_POINT('',(3.79940591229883,-6.5,-2.72814379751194));
#564=CARTESIAN_POINT('',(3.91962359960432,-6.5,-2.66078705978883));
#565=CARTESIAN_POINT('',(4.15815744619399,-6.5,-2.52276484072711));
#566=CARTESIAN_POINT('',(4.27647350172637,-6.5,-2.45209917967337));
#567=CARTESIAN_POINT('',(4.510894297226,-6.5,-2.30816632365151));
#568=CARTESIAN_POINT('',(4.62700566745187,-6.5,-2.23490988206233));
#569=CARTESIAN_POINT('',(4.85758619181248,-6.5,-2.08590677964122));
#570=CARTESIAN_POINT('',(4.97205568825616,-6.5,-2.01016064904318));
#571=CARTESIAN_POINT('',(5.08578643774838,-6.5,-1.93333420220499));
#572=B_SPLINE_CURVE_WITH_KNOTS('',3,(#530,#531,#532,#533,#534,#535,#536,#537,#538,#539,#540,
#541,#542,#543,#544,#545,#546,#547,#548,#549,#550,#551,#552,#553,#554,#555,#556,#557,#558,#559,
#560,#561,#562,#563,#564,#565,#566,#567,#568,#569,#570,#571),.UNSPECIFIED.,.F.,.F.,(4,2,2,2,2,2,
2,2,2,2,2,2,2,2,2,2,2,2,2,2,4),(0.,0.411310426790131,0.822707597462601,1.23564791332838,
1.64856583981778,2.49590493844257,3.34197710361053,3.88772071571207,4.43347311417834,
4.97320018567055,5.51288150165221,6.05421432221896,6.59559510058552,7.1430386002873,
7.69047348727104,8.53748456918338,9.38576777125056,9.79913116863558,10.2125170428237,
10.6243522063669,11.0361002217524),.UNSPECIFIED.);
#573=CARTESIAN_POINT('',(-5.08578643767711,-6.50000000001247,-1.93333420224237));
#574=VERTEX_POINT('',#573);
#575=EDGE_CURVE('E168',#574,#527,#572,.T.);
#576=ORIENTED_EDGE('',*,*,#575,.F.);
#577=CARTESIAN_POINT('',(-6.50000000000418,-5.08578643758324,-1.93333420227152));
#578=CARTESIAN_POINT('',(-6.38258305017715,-5.20320338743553,-1.95544496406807));
#579=CARTESIAN_POINT('',(-6.26464398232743,-5.32114245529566,-1.97213629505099));
#580=CARTESIAN_POINT('',(-6.02876615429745,-5.55702028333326,-1.99438943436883));
#581=CARTESIAN_POINT('',(-5.9108296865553,-5.6749567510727,-2.00000000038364));
#582=CARTESIAN_POINT('',(-5.6749567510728,-5.91082968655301,-2.00000000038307));
#583=CARTESIAN_POINT('',(-5.55702028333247,-6.02876615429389,-1.99438943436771));
#584=CARTESIAN_POINT('',(-5.32114245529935,-6.2646439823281,-1.97213629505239));
#585=CARTESIAN_POINT('',(-5.20320338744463,-6.38258305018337,-1.95544496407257));
#586=CARTESIAN_POINT('',(-5.08578643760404,-6.50000000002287,-1.93333420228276));
#587=B_SPLINE_CURVE_WITH_KNOTS('',3,(#577,#578,#579,#580,#581,#582,#583,#584,#585,#586),
.UNSPECIFIED.,.F.,.F.,(4,2,2,2,4),(0.,0.50249219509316,1.00276834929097,1.50304450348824,
2.00553669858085),.UNSPECIFIED.);
#588=EDGE_CURVE('E202',#435,#574,#587,.T.);
#589=ORIENTED_EDGE('',*,*,#588,.F.);
#590=EDGE_LOOP('',(#437,#452,#499,#512,#513,#514,#529,#576,#589));
#591=FACE_BOUND('',#590,.T.);
#592=ADVANCED_FACE('F177',(#388,#591),#385,.T.);
#593=CARTESIAN_POINT('',(5.22168348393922,5.01421356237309,-6.41150462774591));
#594=DIRECTION('',(0.,1.,0.));
#595=DIRECTION('',(0.,0.,1.));
#596=AXIS2_PLACEMENT_3D('',#593,#594,#595);
#597=PLANE('',#596);
#598=DIRECTION('',(0.,0.,-1.));
#599=VECTOR('',#598,1.);
#600=CARTESIAN_POINT('',(6.7,5.01421356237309,-5.));
#601=LINE('',#600,#599);
#602=CARTESIAN_POINT('',(6.7,5.01421356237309,-4.99999999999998));
#603=VERTEX_POINT('',#602);
#604=CARTESIAN_POINT('',(6.7,5.01421356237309,0.));
#605=VERTEX_POINT('',#604);
#606=EDGE_CURVE('E301',#603,#605,#601,.F.);
#607=ORIENTED_EDGE('',*,*,#606,.F.);
#608=CARTESIAN_POINT('',(1.13061329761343,5.01421356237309,-5.23061329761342));
#609=DIRECTION('',(0.,1.,0.));
#610=DIRECTION('',(0.,0.,1.));
#611=AXIS2_PLACEMENT_3D('',#608,#609,#610);
#612=CIRCLE('',#611,5.57415919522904);
#613=EDGE_CURVE('E262',#228,#603,#612,.F.);
#614=ORIENTED_EDGE('',*,*,#613,.F.);
#615=ORIENTED_EDGE('',*,*,#229,.T.);
#616=ORIENTED_EDGE('',*,*,#117,.T.);
#617=ORIENTED_EDGE('',*,*,#212,.T.);
#618=ORIENTED_EDGE('',*,*,#367,.T.);
#619=DIRECTION('',(1.,0.,0.));
#620=VECTOR('',#619,1.);
#621=CARTESIAN_POINT('',(5.22168348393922,5.01421356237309,0.));
#622=LINE('',#621,#620);
#623=EDGE_CURVE('E52',#360,#605,#622,.T.);
#624=ORIENTED_EDGE('',*,*,#623,.T.);
#625=EDGE_LOOP('',(#607,#614,#615,#616,#617,#618,#624));
#626=FACE_BOUND('',#625,.T.);
#627=ADVANCED_FACE('F182',(#626),#597,.T.);
#628=CARTESIAN_POINT('',(5.22168348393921,-5.08578643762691,-6.41150462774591));
#629=DIRECTION('',(0.,1.,0.));
#630=DIRECTION('',(0.,0.,1.));
#631=AXIS2_PLACEMENT_3D('',#628,#629,#630);
#632=PLANE('',#631);
#633=CARTESIAN_POINT('',(1.13061329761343,-5.08578643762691,-5.23061329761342));
#634=DIRECTION('',(0.,1.,0.));
#635=DIRECTION('',(0.,0.,1.));
#636=AXIS2_PLACEMENT_3D('',#633,#634,#635);
#637=CIRCLE('',#636,5.57415919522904);
#638=CARTESIAN_POINT('',(6.7,-5.08578643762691,-4.99999999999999));
#639=VERTEX_POINT('',#638);
#640=EDGE_CURVE('E374',#639,#311,#637,.T.);
#641=ORIENTED_EDGE('',*,*,#640,.F.);
#642=DIRECTION('',(0.,0.,-1.));
#643=VECTOR('',#642,1.);
#644=CARTESIAN_POINT('',(6.7,-5.08578643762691,-5.));
#645=LINE('',#644,#643);
#646=CARTESIAN_POINT('',(6.7,-5.08578643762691,0.));
#647=VERTEX_POINT('',#646);
#648=EDGE_CURVE('E303',#647,#639,#645,.T.);
#649=ORIENTED_EDGE('',*,*,#648,.F.);
#650=DIRECTION('',(1.,0.,0.));
#651=VECTOR('',#650,1.);
#652=CARTESIAN_POINT('',(5.22168348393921,-5.08578643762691,0.));
#653=LINE('',#652,#651);
#654=CARTESIAN_POINT('',(6.5,-5.08578643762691,0.));
#655=VERTEX_POINT('',#654);
#656=EDGE_CURVE('E360',#655,#647,#653,.T.);
#657=ORIENTED_EDGE('',*,*,#656,.F.);
#658=DIRECTION('',(0.,0.,1.));
#659=VECTOR('',#658,1.);
#660=CARTESIAN_POINT('',(6.5,-5.08578643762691,0.));
#661=LINE('',#660,#659);
#662=EDGE_CURVE('E166',#160,#655,#661,.T.);
#663=ORIENTED_EDGE('',*,*,#662,.F.);
#664=ORIENTED_EDGE('',*,*,#161,.F.);
#665=ORIENTED_EDGE('',*,*,#100,.F.);
#666=ORIENTED_EDGE('',*,*,#318,.F.);
#667=EDGE_LOOP('',(#641,#649,#657,#663,#664,#665,#666));
#668=FACE_BOUND('',#667,.T.);
#669=ADVANCED_FACE('F253',(#668),#632,.F.);
#670=CARTESIAN_POINT('',(1.13061329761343,-5.08578643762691,-5.23061329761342));
#671=DIRECTION('',(0.,1.,0.));
#672=DIRECTION('',(0.,0.,1.));
#673=AXIS2_PLACEMENT_3D('',#670,#671,#672);
#674=CYLINDRICAL_SURFACE('',#673,5.57415919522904);
#675=ORIENTED_EDGE('',*,*,#312,.T.);
#676=ORIENTED_EDGE('',*,*,#335,.T.);
#677=ORIENTED_EDGE('',*,*,#258,.T.);
#678=ORIENTED_EDGE('',*,*,#613,.T.);
#679=DIRECTION('',(0.,1.,0.));
#680=VECTOR('',#679,1.);
#681=CARTESIAN_POINT('',(6.7,-5.08578643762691,-5.));
#682=LINE('',#681,#680);
#683=EDGE_CURVE('E325',#639,#603,#682,.T.);
#684=ORIENTED_EDGE('',*,*,#683,.F.);
#685=ORIENTED_EDGE('',*,*,#640,.T.);
#686=EDGE_LOOP('',(#675,#676,#677,#678,#684,#685));
#687=FACE_BOUND('',#686,.T.);
#688=ADVANCED_FACE('F248',(#687),#674,.T.);
#689=CARTESIAN_POINT('',(6.5,5.08578643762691,0.));
#690=DIRECTION('',(0.707106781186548,0.707106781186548,0.));
#691=DIRECTION('',(-0.707106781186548,0.707106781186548,0.));
#692=AXIS2_PLACEMENT_3D('',#689,#690,#691);
#693=PLANE('',#692);
#694=DIRECTION('',(-0.707106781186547,0.707106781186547,0.));
#695=VECTOR('',#694,1.);
#696=CARTESIAN_POINT('',(6.5,5.08578643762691,0.));
#697=LINE('',#696,#695);
#698=CARTESIAN_POINT('',(5.08578643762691,6.5,0.));
#699=VERTEX_POINT('',#698);
#700=EDGE_CURVE('E323',#350,#699,#697,.T.);
#701=ORIENTED_EDGE('',*,*,#700,.F.);
#702=ORIENTED_EDGE('',*,*,#353,.T.);
#703=ORIENTED_EDGE('',*,*,#511,.T.);
#704=DIRECTION('',(0.,0.,1.));
#705=VECTOR('',#704,1.);
#706=CARTESIAN_POINT('',(5.08578643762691,6.5,0.));
#707=LINE('',#706,#705);
#708=EDGE_CURVE('E352',#699,#497,#707,.F.);
#709=ORIENTED_EDGE('',*,*,#708,.F.);
#710=EDGE_LOOP('',(#701,#702,#703,#709));
#711=FACE_BOUND('',#710,.T.);
#712=ADVANCED_FACE('F244',(#711),#693,.T.);
#713=CARTESIAN_POINT('',(5.08578643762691,6.5,0.));
#714=DIRECTION('',(0.,1.,0.));
#715=DIRECTION('',(0.,0.,1.));
#716=AXIS2_PLACEMENT_3D('',#713,#714,#715);
#717=PLANE('',#716);
#718=DIRECTION('',(1.,0.,0.));
#719=VECTOR('',#718,1.);
#720=CARTESIAN_POINT('',(0.,6.5,0.));
#721=LINE('',#720,#719);
#722=CARTESIAN_POINT('',(-5.0857864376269,6.50000000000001,0.));
#723=VERTEX_POINT('',#722);
#724=EDGE_CURVE('E320',#699,#723,#721,.F.);
#725=ORIENTED_EDGE('',*,*,#724,.F.);
#726=ORIENTED_EDGE('',*,*,#708,.T.);
#727=ORIENTED_EDGE('',*,*,#498,.T.);
#728=DIRECTION('',(0.,0.,1.));
#729=VECTOR('',#728,1.);
#730=CARTESIAN_POINT('',(-5.0857864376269,6.50000000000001,0.));
#731=LINE('',#730,#729);
#732=EDGE_CURVE('E349',#723,#450,#731,.F.);
#733=ORIENTED_EDGE('',*,*,#732,.F.);
#734=EDGE_LOOP('',(#725,#726,#727,#733));
#735=FACE_BOUND('',#734,.T.);
#736=ADVANCED_FACE('F247',(#735),#717,.T.);
#737=CARTESIAN_POINT('',(-5.0857864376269,6.50000000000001,0.));
#738=DIRECTION('',(-0.707106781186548,0.707106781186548,0.));
#739=DIRECTION('',(-0.707106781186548,-0.707106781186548,0.));
#740=AXIS2_PLACEMENT_3D('',#737,#738,#739);
#741=PLANE('',#740);
#742=DIRECTION('',(-0.707106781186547,-0.707106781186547,0.));
#743=VECTOR('',#742,1.);
#744=CARTESIAN_POINT('',(-5.0857864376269,6.50000000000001,0.));
#745=LINE('',#744,#743);
#746=CARTESIAN_POINT('',(-6.5,5.08578643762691,0.));
#747=VERTEX_POINT('',#746);
#748=EDGE_CURVE('E317',#723,#747,#745,.T.);
#749=ORIENTED_EDGE('',*,*,#748,.F.);
#750=ORIENTED_EDGE('',*,*,#732,.T.);
#751=ORIENTED_EDGE('',*,*,#451,.T.);
#752=DIRECTION('',(0.,0.,1.));
#753=VECTOR('',#752,1.);
#754=CARTESIAN_POINT('',(-6.5,5.08578643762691,0.));
#755=LINE('',#754,#753);
#756=EDGE_CURVE('E346',#747,#433,#755,.F.);
#757=ORIENTED_EDGE('',*,*,#756,.F.);
#758=EDGE_LOOP('',(#749,#750,#751,#757));
#759=FACE_BOUND('',#758,.T.);
#760=ADVANCED_FACE('F419',(#759),#741,.T.);
#761=CARTESIAN_POINT('',(-6.5,5.08578643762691,0.));
#762=DIRECTION('',(-1.,0.,0.));
#763=DIRECTION('',(0.,0.,1.));
#764=AXIS2_PLACEMENT_3D('',#761,#762,#763);
#765=PLANE('',#764);
#766=DIRECTION('',(0.,1.,0.));
#767=VECTOR('',#766,1.);
#768=CARTESIAN_POINT('',(-6.5,0.,0.));
#769=LINE('',#768,#767);
#770=CARTESIAN_POINT('',(-6.5,-5.08578643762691,0.));
#771=VERTEX_POINT('',#770);
#772=EDGE_CURVE('E314',#747,#771,#769,.F.);
#773=ORIENTED_EDGE('',*,*,#772,.F.);
#774=ORIENTED_EDGE('',*,*,#756,.T.);
#775=ORIENTED_EDGE('',*,*,#436,.T.);
#776=DIRECTION('',(0.,0.,1.));
#777=VECTOR('',#776,1.);
#778=CARTESIAN_POINT('',(-6.5,-5.08578643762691,0.));
#779=LINE('',#778,#777);
#780=EDGE_CURVE('E343',#771,#435,#779,.F.);
#781=ORIENTED_EDGE('',*,*,#780,.F.);
#782=EDGE_LOOP('',(#773,#774,#775,#781));
#783=FACE_BOUND('',#782,.T.);
#784=ADVANCED_FACE('F422',(#783),#765,.T.);
#785=CARTESIAN_POINT('',(-6.5,-5.08578643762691,0.));
#786=DIRECTION('',(-0.707106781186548,-0.707106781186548,0.));
#787=DIRECTION('',(0.707106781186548,-0.707106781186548,0.));
#788=AXIS2_PLACEMENT_3D('',#785,#786,#787);
#789=PLANE('',#788);
#790=DIRECTION('',(0.707106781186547,-0.707106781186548,0.));
#791=VECTOR('',#790,1.);
#792=CARTESIAN_POINT('',(-6.5,-5.08578643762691,0.));
#793=LINE('',#792,#791);
#794=CARTESIAN_POINT('',(-5.08578643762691,-6.5,0.));
#795=VERTEX_POINT('',#794);
#796=EDGE_CURVE('E311',#771,#795,#793,.T.);
#797=ORIENTED_EDGE('',*,*,#796,.F.);
#798=ORIENTED_EDGE('',*,*,#780,.T.);
#799=ORIENTED_EDGE('',*,*,#588,.T.);
#800=DIRECTION('',(0.,0.,-1.));
#801=VECTOR('',#800,1.);
#802=CARTESIAN_POINT('',(-5.08578643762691,-6.5,0.));
#803=LINE('',#802,#801);
#804=EDGE_CURVE('E167',#795,#574,#803,.T.);
#805=ORIENTED_EDGE('',*,*,#804,.F.);
#806=EDGE_LOOP('',(#797,#798,#799,#805));
#807=FACE_BOUND('',#806,.T.);
#808=ADVANCED_FACE('F396',(#807),#789,.T.);
#809=CARTESIAN_POINT('',(-5.08578643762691,-6.5,0.));
#810=DIRECTION('',(0.,-1.,0.));
#811=DIRECTION('',(0.,0.,-1.));
#812=AXIS2_PLACEMENT_3D('',#809,#810,#811);
#813=PLANE('',#812);
#814=DIRECTION('',(1.,0.,0.));
#815=VECTOR('',#814,1.);
#816=CARTESIAN_POINT('',(0.,-6.5,0.));
#817=LINE('',#816,#815);
#818=CARTESIAN_POINT('',(5.08578643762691,-6.5,0.));
#819=VERTEX_POINT('',#818);
#820=EDGE_CURVE('E308',#795,#819,#817,.T.);
#821=ORIENTED_EDGE('',*,*,#820,.F.);
#822=ORIENTED_EDGE('',*,*,#804,.T.);
#823=ORIENTED_EDGE('',*,*,#575,.T.);
#824=DIRECTION('',(0.,0.,1.));
#825=VECTOR('',#824,1.);
#826=CARTESIAN_POINT('',(5.08578643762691,-6.5,0.));
#827=LINE('',#826,#825);
#828=EDGE_CURVE('E304',#819,#527,#827,.F.);
#829=ORIENTED_EDGE('',*,*,#828,.F.);
#830=EDGE_LOOP('',(#821,#822,#823,#829));
#831=FACE_BOUND('',#830,.T.);
#832=ADVANCED_FACE('F390',(#831),#813,.T.);
#833=CARTESIAN_POINT('',(5.08578643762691,-6.5,0.));
#834=DIRECTION('',(0.707106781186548,-0.707106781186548,0.));
#835=DIRECTION('',(0.707106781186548,0.707106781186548,0.));
#836=AXIS2_PLACEMENT_3D('',#833,#834,#835);
#837=PLANE('',#836);
#838=DIRECTION('',(0.707106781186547,0.707106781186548,0.));
#839=VECTOR('',#838,1.);
#840=CARTESIAN_POINT('',(5.08578643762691,-6.5,0.));
#841=LINE('',#840,#839);
#842=EDGE_CURVE('E43',#819,#655,#841,.T.);
#843=ORIENTED_EDGE('',*,*,#842,.F.);
#844=ORIENTED_EDGE('',*,*,#828,.T.);
#845=ORIENTED_EDGE('',*,*,#528,.T.);
#846=ORIENTED_EDGE('',*,*,#662,.T.);
#847=EDGE_LOOP('',(#843,#844,#845,#846));
#848=FACE_BOUND('',#847,.T.);
#849=ADVANCED_FACE('F174',(#848),#837,.T.);
#850=CARTESIAN_POINT('',(6.7,-5.08578643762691,-5.));
#851=DIRECTION('',(1.,0.,0.));
#852=DIRECTION('',(0.,0.,-1.));
#853=AXIS2_PLACEMENT_3D('',#850,#851,#852);
#854=PLANE('',#853);
#855=ORIENTED_EDGE('',*,*,#648,.T.);
#856=ORIENTED_EDGE('',*,*,#683,.T.);
#857=ORIENTED_EDGE('',*,*,#606,.T.);
#858=DIRECTION('',(0.,1.,0.));
#859=VECTOR('',#858,1.);
#860=CARTESIAN_POINT('',(6.7,0.,0.));
#861=LINE('',#860,#859);
#862=EDGE_CURVE('E11',#647,#605,#861,.T.);
#863=ORIENTED_EDGE('',*,*,#862,.F.);
#864=EDGE_LOOP('',(#855,#856,#857,#863));
#865=FACE_BOUND('',#864,.T.);
#866=ADVANCED_FACE('F377',(#865),#854,.T.);
#867=CARTESIAN_POINT('',(0.,0.,0.));
#868=DIRECTION('',(0.,0.,1.));
#869=DIRECTION('',(1.,0.,0.));
#870=AXIS2_PLACEMENT_3D('',#867,#868,#869);
#871=PLANE('',#870);
#872=CARTESIAN_POINT('',(0.,0.,0.));
#873=DIRECTION('',(0.,0.,1.));
#874=DIRECTION('',(1.,0.,0.));
#875=AXIS2_PLACEMENT_3D('',#872,#873,#874);
#876=CIRCLE('',#875,2.5);
#877=CARTESIAN_POINT('',(2.5,0.,0.));
#878=VERTEX_POINT('',#877);
#879=EDGE_CURVE('E330',#878,#878,#876,.T.);
#880=ORIENTED_EDGE('',*,*,#879,.F.);
#881=EDGE_LOOP('',(#880));
#882=FACE_BOUND('',#881,.T.);
#883=ORIENTED_EDGE('',*,*,#623,.F.);
#884=ORIENTED_EDGE('',*,*,#361,.F.);
#885=ORIENTED_EDGE('',*,*,#700,.T.);
#886=ORIENTED_EDGE('',*,*,#724,.T.);
#887=ORIENTED_EDGE('',*,*,#748,.T.);
#888=ORIENTED_EDGE('',*,*,#772,.T.);
#889=ORIENTED_EDGE('',*,*,#796,.T.);
#890=ORIENTED_EDGE('',*,*,#820,.T.);
#891=ORIENTED_EDGE('',*,*,#842,.T.);
#892=ORIENTED_EDGE('',*,*,#656,.T.);
#893=ORIENTED_EDGE('',*,*,#862,.T.);
#894=EDGE_LOOP('',(#883,#884,#885,#886,#887,#888,#889,#890,#891,#892,#893));
#895=FACE_BOUND('',#894,.T.);
#896=ADVANCED_FACE('F369',(#882,#895),#871,.T.);
#897=CARTESIAN_POINT('',(0.,0.,0.));
#898=DIRECTION('',(0.,0.,1.));
#899=DIRECTION('',(1.,0.,0.));
#900=AXIS2_PLACEMENT_3D('',#897,#898,#899);
#901=CYLINDRICAL_SURFACE('',#900,2.5);
#902=ORIENTED_EDGE('',*,*,#879,.T.);
#903=EDGE_LOOP('',(#902));
#904=FACE_BOUND('',#903,.T.);
#905=ORIENTED_EDGE('',*,*,#31,.F.);
#906=EDGE_LOOP('',(#905));
#907=FACE_BOUND('',#906,.T.);
#908=ADVANCED_FACE('F431',(#904,#907),#901,.F.);
#909=CLOSED_SHELL('',(#46,#148,#216,#268,#322,#339,#380,#592,#627,#669,#688,#712,#736,#760,#784,
#808,#832,#849,#866,#896,#908));
#910=MANIFOLD_SOLID_BREP('B2',#909);
#911=ADVANCED_BREP_SHAPE_REPRESENTATION('',(#18,#910),#14);
#912=SHAPE_DEFINITION_REPRESENTATION(#9,#911);
ENDSEC;
END-ISO-10303-21;
